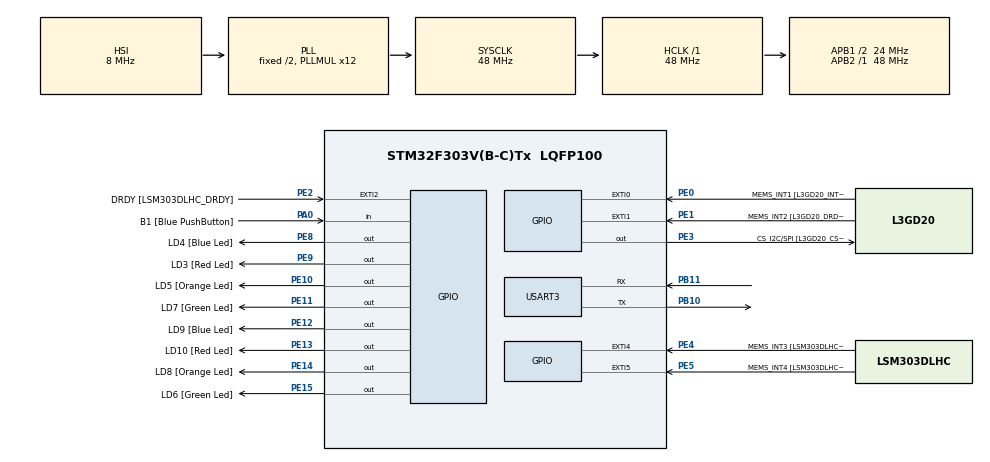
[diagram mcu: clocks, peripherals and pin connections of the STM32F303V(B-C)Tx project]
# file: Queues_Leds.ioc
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Mcu.Family=STM32F3
Mcu.Name=STM32F303V(B-C)Tx
Mcu.Package=LQFP100
NVIC.PriorityGroup=NVIC_PRIORITYGROUP_4
NVIC.TIM6_DAC_IRQn=true\:15\:0\:false\:false\:true\:false\:true\:true
NVIC.TimeBase=TIM6_DAC_IRQn
NVIC.TimeBaseIP=TIM6
NVIC.USART3_IRQn=true\:6\:0\:true\:false\:true\:true\:true\:true
PA0.GPIO_Label=B1 [Blue PushButton]
PA0.GPIO_Mode=GPIO_MODE_INPUT
PA0.GPIO_PuPd=GPIO_NOPULL
PA0.Signal=GPIO_Input
PA11.GPIO_Label=DM
PA11.Signal=USB_DM
PA12.GPIO_Label=DP
PA12.Signal=USB_DP
PA13.GPIO_Label=SWDIO
PA13.Signal=SYS_JTMS-SWDIO
PA14.GPIO_Label=SWCLK
PA14.Signal=SYS_JTCK-SWCLK
PA5.GPIO_Label=SPI1_SCK [L3GD20_SCL/SPC]
PA5.GPIO_Mode=GPIO_MODE_AF_PP
PA5.GPIO_PuPd=GPIO_NOPULL
PA5.GPIO_Speed=GPIO_SPEED_FREQ_LOW
PA5.Signal=SPI1_SCK
PA6.GPIO_Label=SPI1_MISO [L3GD20_SA0/SDO]
PA6.GPIO_Mode=GPIO_MODE_AF_PP
PA6.GPIO_PuPd=GPIO_NOPULL
PA6.GPIO_Speed=GPIO_SPEED_FREQ_LOW
PA6.Signal=SPI1_MISO
PA7.GPIO_Label=SPI1_MISO [L3GD20_SDA/SDI/SDO]
PA7.GPIO_Mode=GPIO_MODE_AF_PP
PA7.GPIO_PuPd=GPIO_NOPULL
PA7.GPIO_Speed=GPIO_SPEED_FREQ_LOW
PA7.Signal=SPI1_MOSI
PB10.Mode=Asynchronous
PB10.Signal=USART3_TX
PB11.Mode=Asynchronous
PB11.Signal=USART3_RX
PB3.GPIO_Label=SWO
PB3.Signal=SYS_JTDO-TRACESWO
PB6.GPIO_FM6=__NULL
PB6.GPIO_Label=I2C1_SCL [LSM303DLHC_SCL]
PB6.GPIO_Mode=GPIO_MODE_AF_OD
PB6.GPIO_PuPd=GPIO_NOPULL
PB6.GPIO_Speed=GPIO_SPEED_FREQ_LOW
PB6.Signal=I2C1_SCL
PB7.GPIO_FM7=__NULL
PB7.GPIO_Label=I2C1_SDA [LSM303DLHC_SDA]
PB7.GPIO_Mode=GPIO_MODE_AF_OD
PB7.GPIO_PuPd=GPIO_NOPULL
PB7.GPIO_Speed=GPIO_SPEED_FREQ_LOW
PB7.Signal=I2C1_SDA
PC14-OSC32_IN.GPIO_Label=OSC32_IN
PC14-OSC32_IN.Signal=RCC_OSC32_IN
PC15-OSC32_OUT.GPIO_Label=OSC32_OUT
PC15-OSC32_OUT.Signal=RCC_OSC32_OUT
PE0.GPIO_Label=MEMS_INT1 [L3GD20_INT1]
PE0.GPIO_ModeDefaultEXTI=GPIO_MODE_EVT_RISING
PE0.GPIO_PuPd=GPIO_NOPULL
PE0.Signal=GPXTI0
PE1.GPIO_Label=MEMS_INT2 [L3GD20_DRDY/INT2]
PE1.GPIO_ModeDefaultEXTI=GPIO_MODE_EVT_RISING
PE1.GPIO_PuPd=GPIO_NOPULL
PE1.Signal=GPXTI1
PE10.GPIO_Label=LD5 [Orange Led]
PE10.GPIO_ModeDefaultOutputPP=GPIO_MODE_OUTPUT_PP
PE10.GPIO_PuPd=GPIO_NOPULL
PE10.GPIO_Speed=GPIO_SPEED_FREQ_LOW
PE10.Signal=GPIO_Output
PE11.GPIO_Label=LD7 [Green Led]
PE11.GPIO_ModeDefaultOutputPP=GPIO_MODE_OUTPUT_PP
PE11.GPIO_PuPd=GPIO_NOPULL
PE11.GPIO_Speed=GPIO_SPEED_FREQ_LOW
PE11.Signal=GPIO_Output
PE12.GPIO_Label=LD9 [Blue Led]
PE12.GPIO_ModeDefaultOutputPP=GPIO_MODE_OUTPUT_PP
PE12.GPIO_PuPd=GPIO_NOPULL
PE12.GPIO_Speed=GPIO_SPEED_FREQ_LOW
PE12.Signal=GPIO_Output
PE13.GPIO_Label=LD10 [Red Led]
PE13.GPIO_ModeDefaultOutputPP=GPIO_MODE_OUTPUT_PP
PE13.GPIO_PuPd=GPIO_NOPULL
PE13.GPIO_Speed=GPIO_SPEED_FREQ_LOW
PE13.Signal=GPIO_Output
PE14.GPIO_Label=LD8 [Orange Led]
PE14.GPIO_ModeDefaultOutputPP=GPIO_MODE_OUTPUT_PP
PE14.GPIO_PuPd=GPIO_NOPULL
PE14.GPIO_Speed=GPIO_SPEED_FREQ_LOW
PE14.Signal=GPIO_Output
PE15.GPIO_Label=LD6 [Green Led]
PE15.GPIO_ModeDefaultOutputPP=GPIO_MODE_OUTPUT_PP
PE15.GPIO_PuPd=GPIO_NOPULL
PE15.GPIO_Speed=GPIO_SPEED_FREQ_LOW
PE15.Signal=GPIO_Output
PE2.GPIO_Label=DRDY [LSM303DLHC_DRDY]
PE2.GPIO_ModeDefaultEXTI=GPIO_MODE_EVT_RISING
PE2.GPIO_PuPd=GPIO_NOPULL
PE2.Signal=GPXTI2
PE3.GPIO_Label=CS_I2C/SPI [L3GD20_CS_I2C/SPI]
PE3.GPIO_ModeDefaultOutputPP=GPIO_MODE_OUTPUT_PP
PE3.GPIO_PuPd=GPIO_NOPULL
PE3.GPIO_Speed=GPIO_SPEED_FREQ_LOW
PE3.Signal=GPIO_Output
PE4.GPIO_Label=MEMS_INT3 [LSM303DLHC_INT1]
PE4.GPIO_ModeDefaultEXTI=GPIO_MODE_EVT_RISING
PE4.GPIO_PuPd=GPIO_NOPULL
PE4.Signal=GPXTI4
PE5.GPIO_Label=MEMS_INT4 [LSM303DLHC_INT2]
PE5.GPIO_ModeDefaultEXTI=GPIO_MODE_EVT_RISING
PE5.GPIO_PuPd=GPIO_NOPULL
PE5.Signal=GPXTI5
PE8.GPIO_Label=LD4 [Blue Led]
PE8.GPIO_ModeDefaultOutputPP=GPIO_MODE_OUTPUT_PP
PE8.GPIO_PuPd=GPIO_NOPULL
PE8.GPIO_Speed=GPIO_SPEED_FREQ_LOW
PE8.Signal=GPIO_Output
PE9.GPIO_Label=LD3 [Red Led]
PE9.GPIO_ModeDefaultOutputPP=GPIO_MODE_OUTPUT_PP
PE9.GPIO_PuPd=GPIO_NOPULL
PE9.GPIO_Speed=GPIO_SPEED_FREQ_LOW
PE9.Signal=GPIO_Output
PF0-OSC_IN.GPIO_Label=OSC_IN
PF0-OSC_IN.Signal=RCC_OSC_IN
PF1-OSC_OUT.GPIO_Label=OSC_OUT
PF1-OSC_OUT.Signal=RCC_OSC_OUT
ProjectManager.HeapSize=0x200
ProjectManager.StackSize=0x400
ProjectManager.TargetToolchain=STM32CubeIDE
RCC.AHBFreq_Value=48000000
RCC.APB1CLKDivider=RCC_HCLK_DIV2
RCC.APB1Freq_Value=24000000
RCC.APB1TimFreq_Value=48000000
RCC.APB2Freq_Value=48000000
RCC.APB2TimFreq_Value=48000000
RCC.CortexFreq_Value=48000000
RCC.HCLKFreq_Value=48000000
RCC.HSE_VALUE=8000000
RCC.HSI_VALUE=8000000
RCC.LSE_VALUE=32768
RCC.PLLMUL=RCC_PLL_MUL12
RCC.SYSCLKFreq_VALUE=48000000
RCC.SYSCLKSourceVirtual=RCC_SYSCLKSOURCE_PLLCLK
RCC.USBFreq_Value=48000000
RTC.HourFormat=RTC_HOURFORMAT_12
USART3.DMADisableonRxErrorParam=ADVFEATURE_DMA_ENABLEONRXERROR
USART3.OverrunDisableParam=ADVFEATURE_OVERRUN_ENABLE
USART3.VirtualMode-Asynchronous=VM_ASYNC
VP_RTC_VS_RTC_Activate.Mode=RTC_Enabled
VP_SYS_VS_tim6.Mode=TIM6
board=STM32F3DISCOVERY

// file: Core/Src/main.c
/* USER CODE BEGIN Header */
/**
  ******************************************************************************
  * @file           : main.c
  * @brief          : Main program body
  ******************************************************************************
  * @attention
  *
  * Copyright (c) 2023 STMicroelectronics.
  * All rights reserved.
  *
  * This software is licensed under terms that can be found in the LICENSE file
  * in the root directory of this software component.
  * If no LICENSE file comes with this software, it is provided AS-IS.
  *
  ******************************************************************************
  */
/* USER CODE END Header */
#include "main.h"

/* USER CODE BEGIN Includes */
#include <stdio.h>
/* USER CODE END Includes */

/* USER CODE BEGIN PD */
#define DWT_CTRL		(*(volatile uint32_t *) 0xE0001000)

#define LED_GREEN_1 	GPIO_PIN_15
#define LED_GREEN_2 	GPIO_PIN_11
#define LED_ORANGE_1 	GPIO_PIN_14
#define LED_ORANGE_2 	GPIO_PIN_10
#define LED_BLUE_1 		GPIO_PIN_12
#define LED_BLUE_2 		GPIO_PIN_8
#define LED_RED_1		GPIO_PIN_13
#define LED_RED_2		GPIO_PIN_9
/* USER CODE END PD */

RTC_HandleTypeDef hrtc;

UART_HandleTypeDef huart3;

/* USER CODE BEGIN PV */
TaskHandle_t LED_handle;
TaskHandle_t MENU_handle;
TaskHandle_t RTC_handle;
TaskHandle_t PRINT_handle;
TaskHandle_t COMMAND_handle;

TaskHandle_t LCD_handle;

QueueHandle_t q_data;
QueueHandle_t q_print;

//volatile uint8_t user_data;
volatile uint8_t user_data;

//state variable
state_t curr_state = sMainMenu;

TimerHandle_t handle_led_timer[4];
TimerHandle_t rtc_timer;

/* USER CODE END PV */

void SystemClock_Config(void);
static void MX_GPIO_Init(void);
static void MX_USART3_UART_Init(void);
static void MX_RTC_Init(void);

int main(void)
{

  /* MCU Configuration--------------------------------------------------------*/

  /* Reset of all peripherals, Initializes the Flash interface and the Systick. */
  HAL_Init();

  /* Configure the system clock */
  SystemClock_Config();

  /* Initialize all configured peripherals */
  MX_GPIO_Init();
  MX_USART3_UART_Init();
  MX_RTC_Init();
  /* USER CODE BEGIN 2 */
	DWT_CTRL |= (1 << 0);

	SEGGER_SYSVIEW_Conf();

	SEGGER_SYSVIEW_Start();

	BaseType_t Status;

	Status = xTaskCreate(MENU_task_handler, "MENU task", 250, "MENU task running", 1, &MENU_handle );
	configASSERT(Status == pdPASS);

	Status = xTaskCreate(LED_task_handler, "LED task", 250, "LED task running", 1, &LED_handle );
	configASSERT(Status == pdPASS);

	Status = xTaskCreate(RTC_task_handler, "RTC task", 250, "RTC task running", 1, &RTC_handle );
	configASSERT(Status == pdPASS);

	Status = xTaskCreate(PRINT_task_handler, "PRINT task", 250, "PRINT task running", 1, &PRINT_handle );
	configASSERT(Status == pdPASS);

	Status = xTaskCreate(COMMAND_task_handler, "COMMAND task", 250, "COMMAND task running", 1, &COMMAND_handle );
	configASSERT(Status == pdPASS);

	Status = xTaskCreate(LCD_task_handler, "LCD task", 250, "LCD task running", 1, &LCD_handle );
	configASSERT(Status == pdPASS);

	q_data = xQueueCreate(10, sizeof(char));

	configASSERT(q_data != NULL);

	q_print = xQueueCreate(10, sizeof(size_t));

	configASSERT(q_print != NULL);

	for(int i = 0; i <4; i++){
		//create software timers for LED effects
		handle_led_timer[i] = xTimerCreate("led_timer", pdMS_TO_TICKS(500), pdTRUE, (void*)(i+1), led_effect_callback);
	}

	rtc_timer = xTimerCreate ("rtc_report_timer",pdMS_TO_TICKS(1000),pdTRUE,NULL,rtc_report_callback);

	HAL_UART_Receive_IT(&huart3, (uint8_t*)&user_data, 1);

	//START SCHEDULER
	vTaskStartScheduler();

  /* USER CODE END 2 */

  /* Infinite loop */
  while (1)
  {

  }
}

void SystemClock_Config(void)
{
  RCC_OscInitTypeDef RCC_OscInitStruct = {0};
  RCC_ClkInitTypeDef RCC_ClkInitStruct = {0};
  RCC_PeriphCLKInitTypeDef PeriphClkInit = {0};

  /** Initializes the RCC Oscillators according to the specified parameters
  * in the RCC_OscInitTypeDef structure.
  */
  RCC_OscInitStruct.OscillatorType = RCC_OSCILLATORTYPE_HSI|RCC_OSCILLATORTYPE_LSI;
  RCC_OscInitStruct.HSIState = RCC_HSI_ON;
  RCC_OscInitStruct.HSICalibrationValue = RCC_HSICALIBRATION_DEFAULT;
  RCC_OscInitStruct.LSIState = RCC_LSI_ON;
  RCC_OscInitStruct.PLL.PLLState = RCC_PLL_ON;
  RCC_OscInitStruct.PLL.PLLSource = RCC_PLLSOURCE_HSI;
  RCC_OscInitStruct.PLL.PLLMUL = RCC_PLL_MUL12;
  if (HAL_RCC_OscConfig(&RCC_OscInitStruct) != HAL_OK)
  {
    Error_Handler();
  }

  /** Initializes the CPU, AHB and APB buses clocks
  */
  RCC_ClkInitStruct.ClockType = RCC_CLOCKTYPE_HCLK|RCC_CLOCKTYPE_SYSCLK
                              |RCC_CLOCKTYPE_PCLK1|RCC_CLOCKTYPE_PCLK2;
  RCC_ClkInitStruct.SYSCLKSource = RCC_SYSCLKSOURCE_PLLCLK;
  RCC_ClkInitStruct.AHBCLKDivider = RCC_SYSCLK_DIV1;
  RCC_ClkInitStruct.APB1CLKDivider = RCC_HCLK_DIV2;
  RCC_ClkInitStruct.APB2CLKDivider = RCC_HCLK_DIV1;

  if (HAL_RCC_ClockConfig(&RCC_ClkInitStruct, FLASH_LATENCY_1) != HAL_OK)
  {
    Error_Handler();
  }
  PeriphClkInit.PeriphClockSelection = RCC_PERIPHCLK_USART3|RCC_PERIPHCLK_RTC;
  PeriphClkInit.Usart3ClockSelection = RCC_USART3CLKSOURCE_PCLK1;
  PeriphClkInit.RTCClockSelection = RCC_RTCCLKSOURCE_LSI;
  if (HAL_RCCEx_PeriphCLKConfig(&PeriphClkInit) != HAL_OK)
  {
    Error_Handler();
  }
}

static void MX_RTC_Init(void)
{

  /** Initialize RTC Only
  */
  hrtc.Instance = RTC;
  hrtc.Init.HourFormat = RTC_HOURFORMAT_12;
  hrtc.Init.AsynchPrediv = 127;
  hrtc.Init.SynchPrediv = 255;
  hrtc.Init.OutPut = RTC_OUTPUT_DISABLE;
  hrtc.Init.OutPutPolarity = RTC_OUTPUT_POLARITY_HIGH;
  hrtc.Init.OutPutType = RTC_OUTPUT_TYPE_OPENDRAIN;
  if (HAL_RTC_Init(&hrtc) != HAL_OK)
  {
    Error_Handler();
  }

}

static void MX_USART3_UART_Init(void)
{

  huart3.Instance = USART3;
  huart3.Init.BaudRate = 38400;
  huart3.Init.WordLength = UART_WORDLENGTH_8B;
  huart3.Init.StopBits = UART_STOPBITS_1;
  huart3.Init.Parity = UART_PARITY_NONE;
  huart3.Init.Mode = UART_MODE_TX_RX;
  huart3.Init.HwFlowCtl = UART_HWCONTROL_NONE;
  huart3.Init.OverSampling = UART_OVERSAMPLING_16;
  huart3.Init.OneBitSampling = UART_ONE_BIT_SAMPLE_DISABLE;
  huart3.AdvancedInit.AdvFeatureInit = UART_ADVFEATURE_NO_INIT;
  if (HAL_UART_Init(&huart3) != HAL_OK)
  {
    Error_Handler();
  }

}

static void MX_GPIO_Init(void)
{
  GPIO_InitTypeDef GPIO_InitStruct = {0};

  /* GPIO Ports Clock Enable */
  __HAL_RCC_GPIOE_CLK_ENABLE();
  __HAL_RCC_GPIOC_CLK_ENABLE();
  __HAL_RCC_GPIOF_CLK_ENABLE();
  __HAL_RCC_GPIOA_CLK_ENABLE();
  __HAL_RCC_GPIOB_CLK_ENABLE();
  __HAL_RCC_GPIOD_CLK_ENABLE();

  /*Configure GPIO pin Output Level */
  HAL_GPIO_WritePin(GPIOE, CS_I2C_SPI_Pin|LD4_Pin|LD3_Pin|LD5_Pin
                          |LD7_Pin|LD9_Pin|LD10_Pin|LD8_Pin
                          |LD6_Pin, GPIO_PIN_RESET);

  /*Configure GPIO pin Output Level */
  HAL_GPIO_WritePin(GPIOD, GPIO_PIN_0|GPIO_PIN_1|GPIO_PIN_2|GPIO_PIN_3
                          |GPIO_PIN_5|GPIO_PIN_6|GPIO_PIN_7, GPIO_PIN_RESET);

  /*Configure GPIO pins : DRDY_Pin MEMS_INT3_Pin MEMS_INT4_Pin MEMS_INT1_Pin
                           MEMS_INT2_Pin */
  GPIO_InitStruct.Pin = DRDY_Pin|MEMS_INT3_Pin|MEMS_INT4_Pin|MEMS_INT1_Pin
                          |MEMS_INT2_Pin;
  GPIO_InitStruct.Mode = GPIO_MODE_EVT_RISING;
  GPIO_InitStruct.Pull = GPIO_NOPULL;
  HAL_GPIO_Init(GPIOE, &GPIO_InitStruct);

  /*Configure GPIO pins : CS_I2C_SPI_Pin LD4_Pin LD3_Pin LD5_Pin
                           LD7_Pin LD9_Pin LD10_Pin LD8_Pin
                           LD6_Pin */
  GPIO_InitStruct.Pin = CS_I2C_SPI_Pin|LD4_Pin|LD3_Pin|LD5_Pin
                          |LD7_Pin|LD9_Pin|LD10_Pin|LD8_Pin
                          |LD6_Pin;
  GPIO_InitStruct.Mode = GPIO_MODE_OUTPUT_PP;
  GPIO_InitStruct.Pull = GPIO_NOPULL;
  GPIO_InitStruct.Speed = GPIO_SPEED_FREQ_LOW;
  HAL_GPIO_Init(GPIOE, &GPIO_InitStruct);

  /*Configure GPIO pin : B1_Pin */
  GPIO_InitStruct.Pin = B1_Pin;
  GPIO_InitStruct.Mode = GPIO_MODE_INPUT;
  GPIO_InitStruct.Pull = GPIO_NOPULL;
  HAL_GPIO_Init(B1_GPIO_Port, &GPIO_InitStruct);

  /*Configure GPIO pins : SPI1_SCK_Pin SPI1_MISO_Pin SPI1_MISOA7_Pin */
  GPIO_InitStruct.Pin = SPI1_SCK_Pin|SPI1_MISO_Pin|SPI1_MISOA7_Pin;
  GPIO_InitStruct.Mode = GPIO_MODE_AF_PP;
  GPIO_InitStruct.Pull = GPIO_NOPULL;
  GPIO_InitStruct.Speed = GPIO_SPEED_FREQ_LOW;
  GPIO_InitStruct.Alternate = GPIO_AF5_SPI1;
  HAL_GPIO_Init(GPIOA, &GPIO_InitStruct);

  /*Configure GPIO pins : DM_Pin DP_Pin */
  GPIO_InitStruct.Pin = DM_Pin|DP_Pin;
  GPIO_InitStruct.Mode = GPIO_MODE_AF_PP;
  GPIO_InitStruct.Pull = GPIO_NOPULL;
  GPIO_InitStruct.Speed = GPIO_SPEED_FREQ_HIGH;
  GPIO_InitStruct.Alternate = GPIO_AF14_USB;
  HAL_GPIO_Init(GPIOA, &GPIO_InitStruct);

  /*Configure GPIO pins : PD0 PD1 PD2 PD3
                           PD5 PD6 PD7 */
  GPIO_InitStruct.Pin = GPIO_PIN_0|GPIO_PIN_1|GPIO_PIN_2|GPIO_PIN_3
                          |GPIO_PIN_5|GPIO_PIN_6|GPIO_PIN_7;
  GPIO_InitStruct.Mode = GPIO_MODE_OUTPUT_PP;
  GPIO_InitStruct.Pull = GPIO_NOPULL;
  GPIO_InitStruct.Speed = GPIO_SPEED_FREQ_LOW;
  HAL_GPIO_Init(GPIOD, &GPIO_InitStruct);

  /*Configure GPIO pins : I2C1_SCL_Pin I2C1_SDA_Pin */
  GPIO_InitStruct.Pin = I2C1_SCL_Pin|I2C1_SDA_Pin;
  GPIO_InitStruct.Mode = GPIO_MODE_AF_OD;
  GPIO_InitStruct.Pull = GPIO_NOPULL;
  GPIO_InitStruct.Speed = GPIO_SPEED_FREQ_LOW;
  GPIO_InitStruct.Alternate = GPIO_AF4_I2C1;
  HAL_GPIO_Init(GPIOB, &GPIO_InitStruct);

}

/* USER CODE BEGIN 4 */

void HAL_UART_RxCpltCallback(UART_HandleTypeDef *huart){
	uint8_t dummy;

	if(! xQueueIsQueueFullFromISR(q_data)){
		//QUEUE IS NOT FULL

		// enqueue data byte
		xQueueSendFromISR(q_data, (void*)&user_data, NULL);

	}else{
		//QUEUE IS FULL
		//check, is user_data == '\n'
		if(user_data == '\r'){
			//make sure that last data byte of the queue is '\n'
			xQueueReceiveFromISR(q_data,(void*)&dummy, NULL);
			xQueueSendFromISR(q_data, (void*)&user_data, NULL);
		}

	}

	//send notification to command handling task if user_data == '\n'
	if( user_data == '\r'){
		xTaskNotifyFromISR(COMMAND_handle, 0, eNoAction, NULL);
	}

	//Enable UART data byte recepction again in IT mode
	HAL_UART_Receive_IT(&huart3, (uint8_t*)&user_data, 1);

}

void led_effect_callback(TimerHandle_t xTimer){
	int ID;

	ID = (uint32_t) pvTimerGetTimerID(xTimer);

	switch(ID){
		case 1:
			LED_effect1();
			break;
		case 2:
			LED_effect2();
			break;
		case 3:
			LED_effect3();
			break;
		case 4:
			LED_effect4();
			break;

	}
}

void rtc_report_callback( TimerHandle_t xTimer )
{
	 show_time_date_itm();

}
/* USER CODE END 4 */

void HAL_TIM_PeriodElapsedCallback(TIM_HandleTypeDef *htim)
{
  if (htim->Instance == TIM6) {
    HAL_IncTick();
  }
}

void Error_Handler(void)
{
  __disable_irq();
  while (1)
  {
  }
}
